VERSION 5.7 ;
BUSBITCHARS "[]" ;
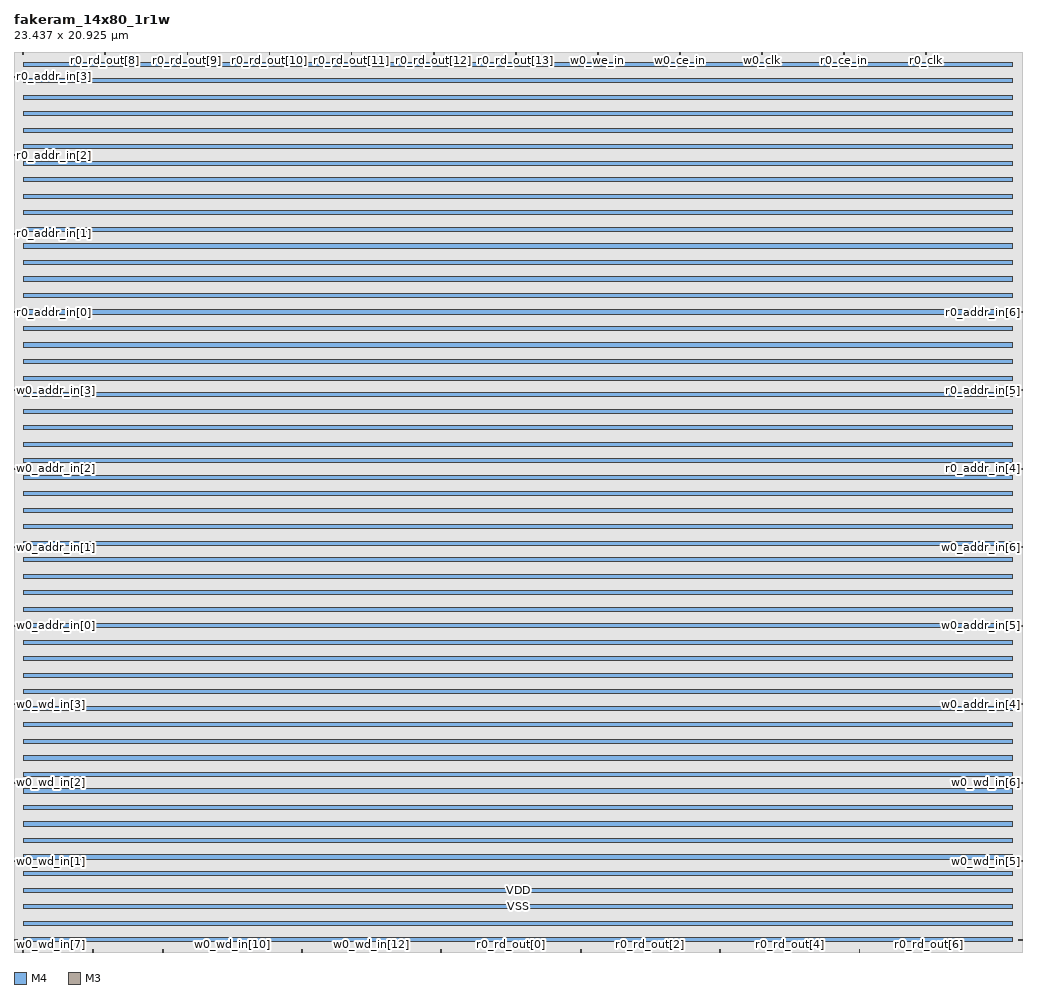
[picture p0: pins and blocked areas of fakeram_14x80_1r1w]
MACRO fakeram_14x80_1r1w
  FOREIGN fakeram_14x80_1r1w 0 0 ;
  SYMMETRY X Y R90 ;
  SIZE 23.437 BY 20.925 ;
  CLASS BLOCK ;
  PIN w0_wd_in[0]
    DIRECTION INPUT ;
    USE SIGNAL ;
    SHAPE ABUTMENT ;
    PORT
      LAYER M4 ;
      RECT 0.000 0.276 0.072 0.300 ;
    END
  END w0_wd_in[0]
  PIN w0_wd_in[1]
    DIRECTION INPUT ;
    USE SIGNAL ;
    SHAPE ABUTMENT ;
    PORT
      LAYER M4 ;
      RECT 0.000 2.100 0.072 2.124 ;
    END
  END w0_wd_in[1]
  PIN w0_wd_in[2]
    DIRECTION INPUT ;
    USE SIGNAL ;
    SHAPE ABUTMENT ;
    PORT
      LAYER M4 ;
      RECT 0.000 3.924 0.072 3.948 ;
    END
  END w0_wd_in[2]
  PIN w0_wd_in[3]
    DIRECTION INPUT ;
    USE SIGNAL ;
    SHAPE ABUTMENT ;
    PORT
      LAYER M4 ;
      RECT 0.000 5.748 0.072 5.772 ;
    END
  END w0_wd_in[3]
  PIN w0_wd_in[4]
    DIRECTION INPUT ;
    USE SIGNAL ;
    SHAPE ABUTMENT ;
    PORT
      LAYER M4 ;
      RECT 23.365 0.276 23.437 0.300 ;
    END
  END w0_wd_in[4]
  PIN w0_wd_in[5]
    DIRECTION INPUT ;
    USE SIGNAL ;
    SHAPE ABUTMENT ;
    PORT
      LAYER M4 ;
      RECT 23.365 2.100 23.437 2.124 ;
    END
  END w0_wd_in[5]
  PIN w0_wd_in[6]
    DIRECTION INPUT ;
    USE SIGNAL ;
    SHAPE ABUTMENT ;
    PORT
      LAYER M4 ;
      RECT 23.365 3.924 23.437 3.948 ;
    END
  END w0_wd_in[6]
  PIN w0_wd_in[7]
    DIRECTION INPUT ;
    USE SIGNAL ;
    SHAPE ABUTMENT ;
    PORT
      LAYER M3 ;
      RECT 0.207 0.000 0.225 0.054 ;
    END
  END w0_wd_in[7]
  PIN w0_wd_in[8]
    DIRECTION INPUT ;
    USE SIGNAL ;
    SHAPE ABUTMENT ;
    PORT
      LAYER M3 ;
      RECT 1.827 0.000 1.845 0.054 ;
    END
  END w0_wd_in[8]
  PIN w0_wd_in[9]
    DIRECTION INPUT ;
    USE SIGNAL ;
    SHAPE ABUTMENT ;
    PORT
      LAYER M3 ;
      RECT 3.447 0.000 3.465 0.054 ;
    END
  END w0_wd_in[9]
  PIN w0_wd_in[10]
    DIRECTION INPUT ;
    USE SIGNAL ;
    SHAPE ABUTMENT ;
    PORT
      LAYER M3 ;
      RECT 5.067 0.000 5.085 0.054 ;
    END
  END w0_wd_in[10]
  PIN w0_wd_in[11]
    DIRECTION INPUT ;
    USE SIGNAL ;
    SHAPE ABUTMENT ;
    PORT
      LAYER M3 ;
      RECT 6.687 0.000 6.705 0.054 ;
    END
  END w0_wd_in[11]
  PIN w0_wd_in[12]
    DIRECTION INPUT ;
    USE SIGNAL ;
    SHAPE ABUTMENT ;
    PORT
      LAYER M3 ;
      RECT 8.307 0.000 8.325 0.054 ;
    END
  END w0_wd_in[12]
  PIN w0_wd_in[13]
    DIRECTION INPUT ;
    USE SIGNAL ;
    SHAPE ABUTMENT ;
    PORT
      LAYER M3 ;
      RECT 9.927 0.000 9.945 0.054 ;
    END
  END w0_wd_in[13]
  PIN r0_rd_out[0]
    DIRECTION OUTPUT ;
    USE SIGNAL ;
    SHAPE ABUTMENT ;
    PORT
      LAYER M3 ;
      RECT 11.547 0.000 11.565 0.054 ;
    END
  END r0_rd_out[0]
  PIN r0_rd_out[1]
    DIRECTION OUTPUT ;
    USE SIGNAL ;
    SHAPE ABUTMENT ;
    PORT
      LAYER M3 ;
      RECT 13.167 0.000 13.185 0.054 ;
    END
  END r0_rd_out[1]
  PIN r0_rd_out[2]
    DIRECTION OUTPUT ;
    USE SIGNAL ;
    SHAPE ABUTMENT ;
    PORT
      LAYER M3 ;
      RECT 14.787 0.000 14.805 0.054 ;
    END
  END r0_rd_out[2]
  PIN r0_rd_out[3]
    DIRECTION OUTPUT ;
    USE SIGNAL ;
    SHAPE ABUTMENT ;
    PORT
      LAYER M3 ;
      RECT 16.407 0.000 16.425 0.054 ;
    END
  END r0_rd_out[3]
  PIN r0_rd_out[4]
    DIRECTION OUTPUT ;
    USE SIGNAL ;
    SHAPE ABUTMENT ;
    PORT
      LAYER M3 ;
      RECT 18.027 0.000 18.045 0.054 ;
    END
  END r0_rd_out[4]
  PIN r0_rd_out[5]
    DIRECTION OUTPUT ;
    USE SIGNAL ;
    SHAPE ABUTMENT ;
    PORT
      LAYER M3 ;
      RECT 19.647 0.000 19.665 0.054 ;
    END
  END r0_rd_out[5]
  PIN r0_rd_out[6]
    DIRECTION OUTPUT ;
    USE SIGNAL ;
    SHAPE ABUTMENT ;
    PORT
      LAYER M3 ;
      RECT 21.267 0.000 21.285 0.054 ;
    END
  END r0_rd_out[6]
  PIN r0_rd_out[7]
    DIRECTION OUTPUT ;
    USE SIGNAL ;
    SHAPE ABUTMENT ;
    PORT
      LAYER M3 ;
      RECT 0.207 20.871 0.225 20.925 ;
    END
  END r0_rd_out[7]
  PIN r0_rd_out[8]
    DIRECTION OUTPUT ;
    USE SIGNAL ;
    SHAPE ABUTMENT ;
    PORT
      LAYER M3 ;
      RECT 2.115 20.871 2.133 20.925 ;
    END
  END r0_rd_out[8]
  PIN r0_rd_out[9]
    DIRECTION OUTPUT ;
    USE SIGNAL ;
    SHAPE ABUTMENT ;
    PORT
      LAYER M3 ;
      RECT 4.023 20.871 4.041 20.925 ;
    END
  END r0_rd_out[9]
  PIN r0_rd_out[10]
    DIRECTION OUTPUT ;
    USE SIGNAL ;
    SHAPE ABUTMENT ;
    PORT
      LAYER M3 ;
      RECT 5.931 20.871 5.949 20.925 ;
    END
  END r0_rd_out[10]
  PIN r0_rd_out[11]
    DIRECTION OUTPUT ;
    USE SIGNAL ;
    SHAPE ABUTMENT ;
    PORT
      LAYER M3 ;
      RECT 7.839 20.871 7.857 20.925 ;
    END
  END r0_rd_out[11]
  PIN r0_rd_out[12]
    DIRECTION OUTPUT ;
    USE SIGNAL ;
    SHAPE ABUTMENT ;
    PORT
      LAYER M3 ;
      RECT 9.747 20.871 9.765 20.925 ;
    END
  END r0_rd_out[12]
  PIN r0_rd_out[13]
    DIRECTION OUTPUT ;
    USE SIGNAL ;
    SHAPE ABUTMENT ;
    PORT
      LAYER M3 ;
      RECT 11.655 20.871 11.673 20.925 ;
    END
  END r0_rd_out[13]
  PIN w0_addr_in[0]
    DIRECTION INPUT ;
    USE SIGNAL ;
    SHAPE ABUTMENT ;
    PORT
      LAYER M4 ;
      RECT 0.000 7.572 0.072 7.596 ;
    END
  END w0_addr_in[0]
  PIN w0_addr_in[1]
    DIRECTION INPUT ;
    USE SIGNAL ;
    SHAPE ABUTMENT ;
    PORT
      LAYER M4 ;
      RECT 0.000 9.396 0.072 9.420 ;
    END
  END w0_addr_in[1]
  PIN w0_addr_in[2]
    DIRECTION INPUT ;
    USE SIGNAL ;
    SHAPE ABUTMENT ;
    PORT
      LAYER M4 ;
      RECT 0.000 11.220 0.072 11.244 ;
    END
  END w0_addr_in[2]
  PIN w0_addr_in[3]
    DIRECTION INPUT ;
    USE SIGNAL ;
    SHAPE ABUTMENT ;
    PORT
      LAYER M4 ;
      RECT 0.000 13.044 0.072 13.068 ;
    END
  END w0_addr_in[3]
  PIN w0_addr_in[4]
    DIRECTION INPUT ;
    USE SIGNAL ;
    SHAPE ABUTMENT ;
    PORT
      LAYER M4 ;
      RECT 23.365 5.748 23.437 5.772 ;
    END
  END w0_addr_in[4]
  PIN w0_addr_in[5]
    DIRECTION INPUT ;
    USE SIGNAL ;
    SHAPE ABUTMENT ;
    PORT
      LAYER M4 ;
      RECT 23.365 7.572 23.437 7.596 ;
    END
  END w0_addr_in[5]
  PIN w0_addr_in[6]
    DIRECTION INPUT ;
    USE SIGNAL ;
    SHAPE ABUTMENT ;
    PORT
      LAYER M4 ;
      RECT 23.365 9.396 23.437 9.420 ;
    END
  END w0_addr_in[6]
  PIN r0_addr_in[0]
    DIRECTION INPUT ;
    USE SIGNAL ;
    SHAPE ABUTMENT ;
    PORT
      LAYER M4 ;
      RECT 0.000 14.868 0.072 14.892 ;
    END
  END r0_addr_in[0]
  PIN r0_addr_in[1]
    DIRECTION INPUT ;
    USE SIGNAL ;
    SHAPE ABUTMENT ;
    PORT
      LAYER M4 ;
      RECT 0.000 16.692 0.072 16.716 ;
    END
  END r0_addr_in[1]
  PIN r0_addr_in[2]
    DIRECTION INPUT ;
    USE SIGNAL ;
    SHAPE ABUTMENT ;
    PORT
      LAYER M4 ;
      RECT 0.000 18.516 0.072 18.540 ;
    END
  END r0_addr_in[2]
  PIN r0_addr_in[3]
    DIRECTION INPUT ;
    USE SIGNAL ;
    SHAPE ABUTMENT ;
    PORT
      LAYER M4 ;
      RECT 0.000 20.340 0.072 20.364 ;
    END
  END r0_addr_in[3]
  PIN r0_addr_in[4]
    DIRECTION INPUT ;
    USE SIGNAL ;
    SHAPE ABUTMENT ;
    PORT
      LAYER M4 ;
      RECT 23.365 11.220 23.437 11.244 ;
    END
  END r0_addr_in[4]
  PIN r0_addr_in[5]
    DIRECTION INPUT ;
    USE SIGNAL ;
    SHAPE ABUTMENT ;
    PORT
      LAYER M4 ;
      RECT 23.365 13.044 23.437 13.068 ;
    END
  END r0_addr_in[5]
  PIN r0_addr_in[6]
    DIRECTION INPUT ;
    USE SIGNAL ;
    SHAPE ABUTMENT ;
    PORT
      LAYER M4 ;
      RECT 23.365 14.868 23.437 14.892 ;
    END
  END r0_addr_in[6]
  PIN w0_we_in
    DIRECTION INPUT ;
    USE SIGNAL ;
    SHAPE ABUTMENT ;
    PORT
      LAYER M3 ;
      RECT 13.563 20.871 13.581 20.925 ;
    END
  END w0_we_in
  PIN w0_ce_in
    DIRECTION INPUT ;
    USE SIGNAL ;
    SHAPE ABUTMENT ;
    PORT
      LAYER M3 ;
      RECT 15.471 20.871 15.489 20.925 ;
    END
  END w0_ce_in
  PIN w0_clk
    DIRECTION INPUT ;
    USE SIGNAL ;
    SHAPE ABUTMENT ;
    PORT
      LAYER M3 ;
      RECT 17.379 20.871 17.397 20.925 ;
    END
  END w0_clk
  PIN r0_ce_in
    DIRECTION INPUT ;
    USE SIGNAL ;
    SHAPE ABUTMENT ;
    PORT
      LAYER M3 ;
      RECT 19.287 20.871 19.305 20.925 ;
    END
  END r0_ce_in
  PIN r0_clk
    DIRECTION INPUT ;
    USE SIGNAL ;
    SHAPE ABUTMENT ;
    PORT
      LAYER M3 ;
      RECT 21.195 20.871 21.213 20.925 ;
    END
  END r0_clk
  PIN VSS
    DIRECTION INOUT ;
    USE GROUND ;
    PORT
      LAYER M4 ;
      RECT 0.216 0.240 23.221 0.336 ;
      RECT 0.216 1.008 23.221 1.104 ;
      RECT 0.216 1.776 23.221 1.872 ;
      RECT 0.216 2.544 23.221 2.640 ;
      RECT 0.216 3.312 23.221 3.408 ;
      RECT 0.216 4.080 23.221 4.176 ;
      RECT 0.216 4.848 23.221 4.944 ;
      RECT 0.216 5.616 23.221 5.712 ;
      RECT 0.216 6.384 23.221 6.480 ;
      RECT 0.216 7.152 23.221 7.248 ;
      RECT 0.216 7.920 23.221 8.016 ;
      RECT 0.216 8.688 23.221 8.784 ;
      RECT 0.216 9.456 23.221 9.552 ;
      RECT 0.216 10.224 23.221 10.320 ;
      RECT 0.216 10.992 23.221 11.088 ;
      RECT 0.216 11.760 23.221 11.856 ;
      RECT 0.216 12.528 23.221 12.624 ;
      RECT 0.216 13.296 23.221 13.392 ;
      RECT 0.216 14.064 23.221 14.160 ;
      RECT 0.216 14.832 23.221 14.928 ;
      RECT 0.216 15.600 23.221 15.696 ;
      RECT 0.216 16.368 23.221 16.464 ;
      RECT 0.216 17.136 23.221 17.232 ;
      RECT 0.216 17.904 23.221 18.000 ;
      RECT 0.216 18.672 23.221 18.768 ;
      RECT 0.216 19.440 23.221 19.536 ;
      RECT 0.216 20.208 23.221 20.304 ;
    END
  END VSS
  PIN VDD
    DIRECTION INOUT ;
    USE POWER ;
    PORT
      LAYER M4 ;
      RECT 0.216 0.624 23.221 0.720 ;
      RECT 0.216 1.392 23.221 1.488 ;
      RECT 0.216 2.160 23.221 2.256 ;
      RECT 0.216 2.928 23.221 3.024 ;
      RECT 0.216 3.696 23.221 3.792 ;
      RECT 0.216 4.464 23.221 4.560 ;
      RECT 0.216 5.232 23.221 5.328 ;
      RECT 0.216 6.000 23.221 6.096 ;
      RECT 0.216 6.768 23.221 6.864 ;
      RECT 0.216 7.536 23.221 7.632 ;
      RECT 0.216 8.304 23.221 8.400 ;
      RECT 0.216 9.072 23.221 9.168 ;
      RECT 0.216 9.840 23.221 9.936 ;
      RECT 0.216 10.608 23.221 10.704 ;
      RECT 0.216 11.376 23.221 11.472 ;
      RECT 0.216 12.144 23.221 12.240 ;
      RECT 0.216 12.912 23.221 13.008 ;
      RECT 0.216 13.680 23.221 13.776 ;
      RECT 0.216 14.448 23.221 14.544 ;
      RECT 0.216 15.216 23.221 15.312 ;
      RECT 0.216 15.984 23.221 16.080 ;
      RECT 0.216 16.752 23.221 16.848 ;
      RECT 0.216 17.520 23.221 17.616 ;
      RECT 0.216 18.288 23.221 18.384 ;
      RECT 0.216 19.056 23.221 19.152 ;
      RECT 0.216 19.824 23.221 19.920 ;
      RECT 0.216 20.592 23.221 20.688 ;
    END
  END VDD
  OBS
    LAYER M1 ;
    RECT 0 0 23.437 20.925 ;
    LAYER M2 ;
    RECT 0 0 23.437 20.925 ;
    LAYER M3 ;
    RECT 0 0 23.437 20.925 ;
    LAYER M4 ;
    RECT 0 0 23.437 20.925 ;
  END
END fakeram_14x80_1r1w

END LIBRARY
